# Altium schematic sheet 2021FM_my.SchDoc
size A4

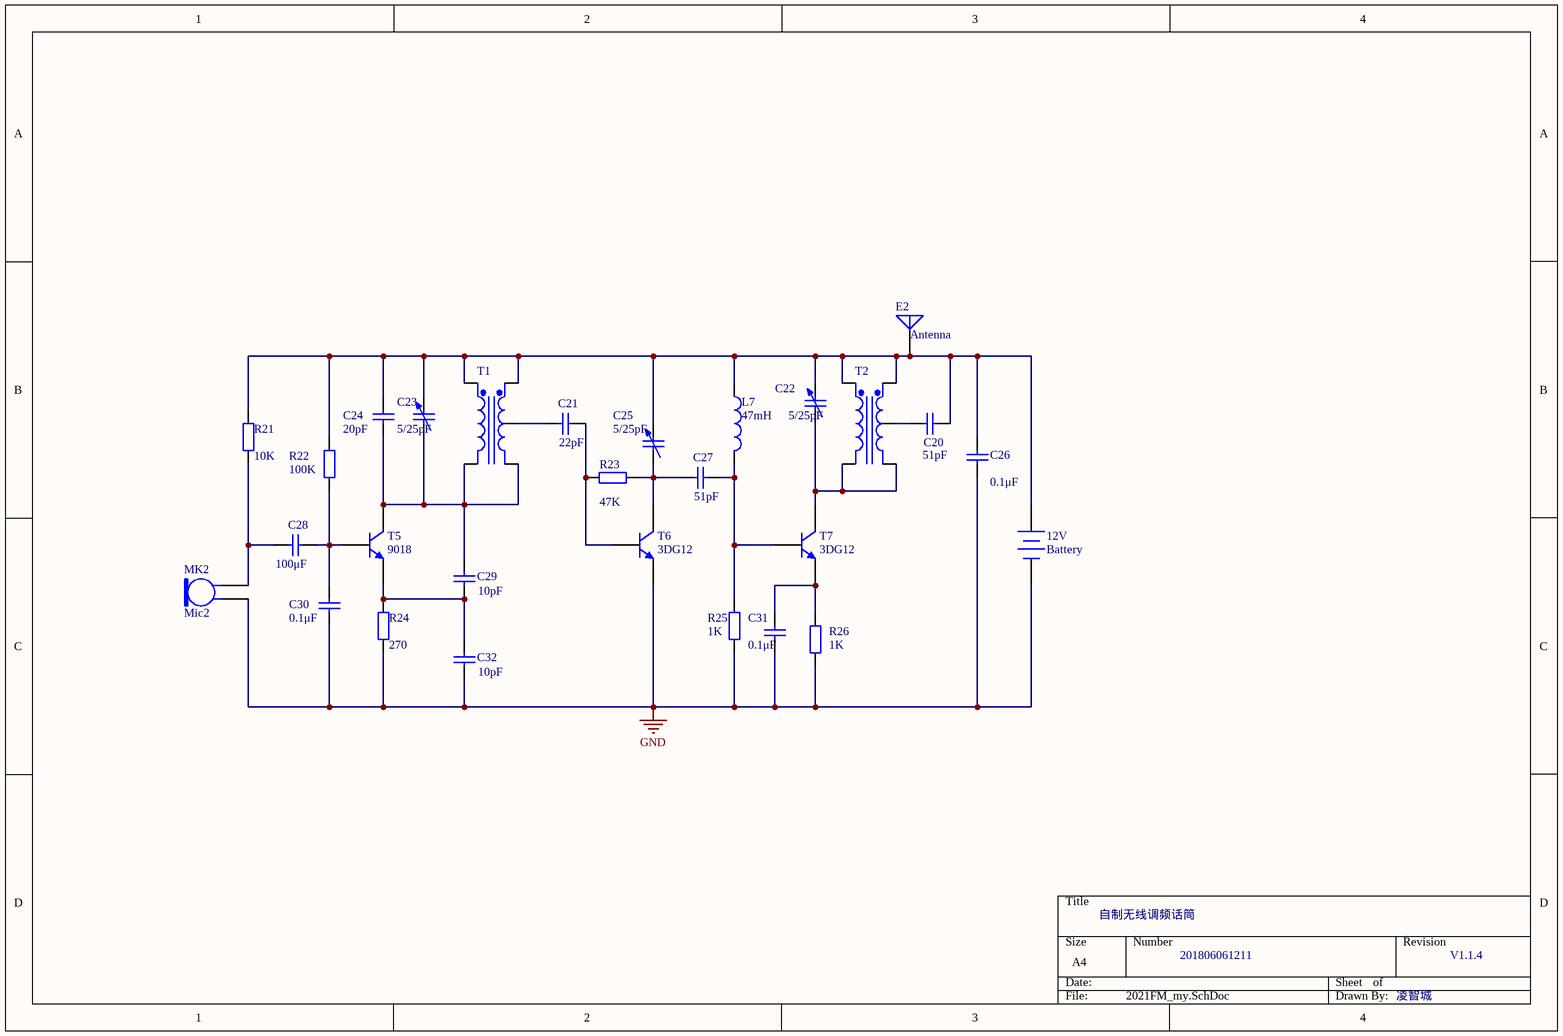
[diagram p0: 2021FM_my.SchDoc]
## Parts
12V  Battery  [BAT-2]
C20  value 51pF  [RAD-0.3]  (hidden comment: Cap)
C21  value 22pF  [RAD-0.3]  (hidden comment: Cap)
C22  value 5/25pF  [C1210_N]  (hidden comment: Cap Var)
C23  value 5/25pF  [C1210_N]  (hidden comment: Cap Var)
C24  value 20pF  [RAD-0.3]  (hidden comment: Cap)
C25  value 5/25pF  [C1210_N]  (hidden comment: Cap Var)
C26  value 0.1μF  [RAD-0.3]  (hidden comment: Cap)
C27  value 51pF  [RAD-0.3]  (hidden comment: Cap)
C28  value 100μF  [RAD-0.3]  (hidden comment: Cap)
C29  value 10pF  [RAD-0.3]  (hidden comment: Cap)
C30  value 0.1μF  [RAD-0.3]  (hidden comment: Cap)
C31  value 0.1μF  [RAD-0.3]  (hidden comment: Cap)
C32  value 10pF  [RAD-0.3]  (hidden comment: Cap)
E2  Antenna  [PIN1]
L7  value 47mH  [INDUCTOR]  (hidden comment: Inductor)
MK2  Mic2  [Microphone]
R21  value 10K  [AXIAL-0.4]  (hidden comment: Res2)
R22  value 100K  [AXIAL-0.4]  (hidden comment: Res2)
R23  value 47K  [AXIAL-0.4]  (hidden comment: Res2)
R24  value 270  [AXIAL-0.4]  (hidden comment: Res2)
R25  value 1K  [AXIAL-0.4]  (hidden comment: Res2)
R26  value 1K  [AXIAL-0.4]  (hidden comment: Res2)
T1  Trans CT Ideal  [TRF_5]  (value not drawn)
T2  Trans CT Ideal  [TRF_5]  (value not drawn)
T5  9018  [three]
T6  3DG12  [three]
T7  3DG12  [three]

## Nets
GND: 12V.2(-) C26.1 C30.1 C31.1 C32.1 MK2.1 R24.1 R25.1 R26.1 T6.3(E)
Net12V_1: 12V.1(+) C20.2 C22.2 C23.2 C24.2 C25.2 C26.2 E2.1(A) L7.1 R21.2 R22.2 T1.1(Pri+) T1.3(Sec+) T2.1(Pri+) T2.3(Sec+)
NetC20_1: C20.1 T2.4(SecCT)
NetC21_1: C21.1 T1.4(SecCT)
NetC21_2: C21.2 R23.1 T6.2(B)
NetC22_1: C22.1 T2.2(Pri-) T2.5(Sec-) T7.1(C)
NetC23_1: C23.1 C24.1 C29.2 T1.2(Pri-) T1.5(Sec-) T5.1(C)
NetC25_1: C25.1 C27.1 R23.2 T6.1(C)
NetC27_2: C27.2 L7.2 R25.2 T7.2(B)
NetC28_1: C28.1 MK2.2 R21.1
NetC28_2: C28.2 C30.2 R22.1 T5.2(B)
NetC29_1: C29.1 C32.2 R24.2 T5.3(E)
NetC31_2: C31.2 R26.2 T7.3(E)

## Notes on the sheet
- 自制无线调频话筒
- 201806061211
- V1.1.4
- 凌智城

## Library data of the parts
12V = Battery: Multicell Battery
C20 C21 C24 C26-C32 = Cap: Capacitor
C22 C23 C25 = Cap Var: Variable or Adjustable Capacitor
E2 = Antenna: Generic Antenna
L7 = Inductor: Code_IEC: 1005
MK2 = Mic2: Microphone
R21-R26 = Res2: Resistor
T1 T2 = Trans CT Ideal: Center-Tapped Transformer (Ideal)
T5-T7 = NPN: NPN Bipolar Transistor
